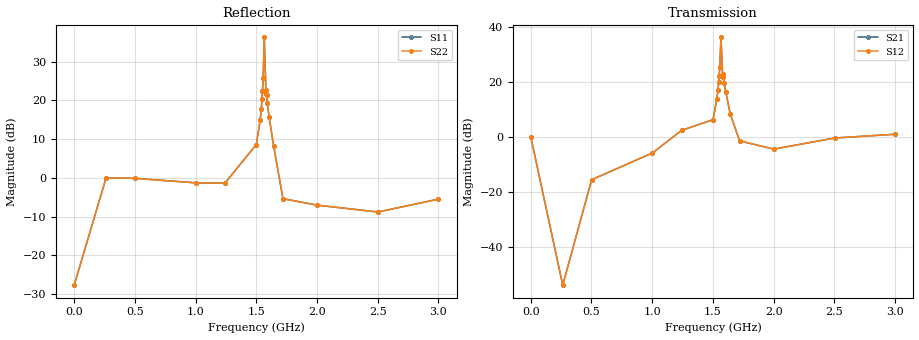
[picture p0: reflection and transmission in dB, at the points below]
!s-Parameter Generated by FASTRON Sdn. Bhd.
!FASTRON P/N : MICC-R68X
!Keysight Technologies,E4991B,MY54100416,A.01.15
!Date: Fri Aug 21 11:30:46 2026
!Version  : Rev00 Fri Aug 21 11:30:46 2026
!Data & Calibration Information:
!PortZ  Port1:50+j0  Port2:50+j0
!When reading, reference impedance value at option line is always used.
! Remarks : This data is being provided solely for informational purposes.
!Freq	S11	S21	S12	S22
# Hz S dB R 50
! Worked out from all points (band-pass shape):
!   1601 points, 1 MHz to 3 GHz, reference 50 ohm
!   highest |S21| = 36.38 dB at 1.566 GHz (marker M1); lowest = -54.0 dB at 263.4 MHz (marker M2)
!   |S21| within 3 dB of the highest: 1.563628 GHz to 1.568192 GHz (4.564 MHz wide, 0.291 % of centre)
!   lowest |S11| = -27.7 dB at 1 MHz (marker M3), VSWR 1.09, Z = 50.4 + j4.11 ohm
!   |S11| at or under -10 dB: start of sweep to 8.414 MHz
!   |S22| runs from -27.7 to 36.3 dB; largest |S21 - S12| = 0
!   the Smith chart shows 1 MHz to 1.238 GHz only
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1000000  -27.72 81.6  -0.05 -2.3  -0.05 -2.3  -27.72 81.6
2.634125e8  -0.02 0.0  -53.96 -7.3  -53.96 -7.3  -0.02 0.0
5.014581e8  -0.14 -9.6  -15.53 79.7  -15.53 79.7  -0.14 -9.6
1.001916e9  -1.30 -31.0  -5.77 59.4  -5.77 59.4  -1.30 -31.0
1.241836e9  -1.39 -91.5  2.48 39.8  2.48 39.8  -1.39 -91.5
1.5005e9  8.60 -43.3  6.36 117.4  6.36 117.4  8.60 -43.3
1.532364e9  14.95 -48.0  13.94 123.4  13.94 123.4  14.95 -48.0
1.541736e9  17.89 -54.5  17.28 119.1  17.28 119.1  17.89 -54.5
1.547359e9  20.44 -58.8  20.03 116.3  20.03 116.3  20.44 -58.8
1.551108e9  22.45 -61.9  22.16 114.2  22.16 114.2  22.45 -61.9
1.556731e9  25.87 -64.6  25.69 112.8  25.69 112.8  25.87 -64.6
1.566103e9  36.27 -143.6  36.38 35.9  36.38 35.9  36.27 -143.6
1.579224e9  22.65 136.5  23.11 -40.7  23.11 -40.7  22.65 136.5
1.582972e9  21.73 132.6  22.22 -44.1  22.22 -44.1  21.73 132.6
1.584847e9  21.27 130.8  21.76 -45.7  21.76 -45.7  21.27 130.8
1.59047e9  19.30 129.1  19.91 -46.4  19.91 -46.4  19.30 129.1
1.605465e9  15.79 117.0  16.49 -55.3  16.49 -55.3  15.79 117.0
1.642952e9  8.23 81.5  8.38 -76.4  8.38 -76.4  8.23 81.5
1.719802e9  -5.39 58.7  -1.37 -32.5  -1.37 -32.5  -5.39 58.7
2.000958e9  -7.06 -20.6  -4.36 14.9  -4.36 14.9  -7.06 -20.6
2.501416e9  -8.83 -73.8  -0.32 21.1  -0.32 21.1  -8.83 -73.8
3e9  -5.51 -89.8  1.06 28.0  1.06 28.0  -5.51 -89.8
